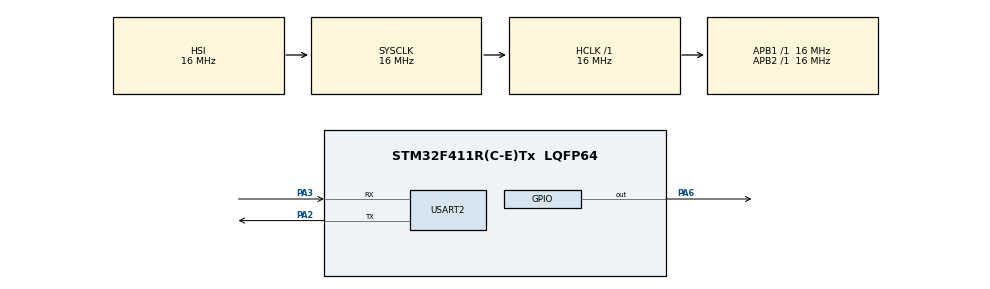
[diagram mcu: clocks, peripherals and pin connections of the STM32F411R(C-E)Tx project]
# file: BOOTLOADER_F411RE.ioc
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Mcu.Family=STM32F4
Mcu.Name=STM32F411R(C-E)Tx
Mcu.Package=LQFP64
NVIC.PriorityGroup=NVIC_PRIORITYGROUP_4
PA13.Mode=Serial_Wire
PA13.Signal=SYS_JTMS-SWDIO
PA14.Mode=Serial_Wire
PA14.Signal=SYS_JTCK-SWCLK
PA2.Mode=Asynchronous
PA2.Signal=USART2_TX
PA3.Mode=Asynchronous
PA3.Signal=USART2_RX
PA6.Signal=GPIO_Output
ProjectManager.HeapSize=0x200
ProjectManager.StackSize=0x400
ProjectManager.TargetToolchain=STM32CubeIDE
RCC.AHBFreq_Value=16000000
RCC.APB1Freq_Value=16000000
RCC.APB2Freq_Value=16000000
RCC.CortexFreq_Value=16000000
RCC.HSE_VALUE=25000000
RCC.HSI_VALUE=16000000
RCC.LSE_VALUE=32768
RCC.SYSCLKFreq_VALUE=16000000
RCC.VCOOutputFreq_Value=192000000
USART2.VirtualMode=VM_ASYNC
board=custom

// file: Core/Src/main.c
/* USER CODE END Header */
#include "main.h"

/* USER CODE BEGIN Includes */
#include "bl_jump.h"
#include <string.h>
#include "bl_ota.h"
#include "ota_image.h"
/* USER CODE END Includes */

UART_HandleTypeDef huart2;

void SystemClock_Config(void);
static void MX_GPIO_Init(void);
static void MX_USART2_UART_Init(void);

/* USER CODE BEGIN 0 */

static uint32_t mem_base = 0;  // used with external or dual flash
static uint32_t mem_cursor = 0;
static uint32_t ota_image_total_size = 16;  // expected OTA Header size

void ota_mem_set_total_size(uint32_t size)
{
    ota_image_total_size = size;
}

int ota_read_mem(uint8_t *buf, uint32_t len)
{
    if (mem_cursor + len > ota_image_total_size)
        return -1;

    memcpy(buf, &ota_image_bin[mem_base + mem_cursor], len);  // this function should be replaced accordingly

    mem_cursor += len;
    return 0;
}

/* USER CODE END 0 */

int main(void)
{

  /* MCU Configuration--------------------------------------------------------*/

  /* Reset of all peripherals, Initializes the Flash interface and the Systick. */
  HAL_Init();

  /* Configure the system clock */
  SystemClock_Config();

  /* Initialize all configured peripherals */
  MX_GPIO_Init();
  MX_USART2_UART_Init();
  /* USER CODE BEGIN 2 */

  HAL_Delay(100);

  HAL_UART_Transmit(&huart2, (uint8_t *)"Inside Bootloader!!\r\n", 21, 100);

  if (check_ota_request() == 0)
  {
	  HAL_UART_Transmit(&huart2, (uint8_t *)"Performing OTA...\n", 18, 100);

	  ota_stream_t stream =
	  {
	      .read = ota_read_mem,
	      .set_total_size = ota_mem_set_total_size
	  };

	  bl_ota_ctx_t ctx;
	 if (bl_ota_run(&ctx, &stream) != 0)
	 {
		 HAL_UART_Transmit(&huart2, (uint8_t *)"OTA Failed...\n", 14, 100);
		  while (1)
		  {
			  HAL_GPIO_TogglePin(GPIOA, GPIO_PIN_5);
			  HAL_Delay(250);
		  }
	 }
	 else {
		 HAL_UART_Transmit(&huart2, (uint8_t *)"OTA Flashed Successfully, Jumping to app...\n", 44, 100);
	 }

  }
  int err = bootloader_is_app_valid();
  if (err != 0)
  {
	  HAL_UART_Transmit(&huart2, (uint8_t *)"Failed to Jump!! ", 17, 100);
	  switch (err){
	  case 1:
		  HAL_UART_Transmit(&huart2, (uint8_t *)"MAGIC ERROR!!\r\n", 15, 100);
		  break;

	  case 2:
		  HAL_UART_Transmit(&huart2, (uint8_t *)"RESET ERROR!!\r\n", 15, 100);
		  break;

	  case 3:
		  HAL_UART_Transmit(&huart2, (uint8_t *)"SIZE ERROR!!\r\n", 14, 100);
		  break;

	  case 4:
		  HAL_UART_Transmit(&huart2, (uint8_t *)"CRC ERROR!!\r\n", 13, 100);
		  break;

	  default:
		  HAL_UART_Transmit(&huart2, (uint8_t *)"ERROR!!\r\n", 9, 100);
		  break;
	  }

	  while (1)
	  {
		  HAL_GPIO_TogglePin(GPIOA, GPIO_PIN_5);
		  HAL_Delay(100);
	  }
  }

  JumpToApplication();

  /* USER CODE END 2 */

  /* Infinite loop */
  while (1)
  {

  }
}

void SystemClock_Config(void)
{
  RCC_OscInitTypeDef RCC_OscInitStruct = {0};
  RCC_ClkInitTypeDef RCC_ClkInitStruct = {0};

  /** Configure the main internal regulator output voltage
  */
  __HAL_RCC_PWR_CLK_ENABLE();
  __HAL_PWR_VOLTAGESCALING_CONFIG(PWR_REGULATOR_VOLTAGE_SCALE3);

  /** Initializes the RCC Oscillators according to the specified parameters
  * in the RCC_OscInitTypeDef structure.
  */
  RCC_OscInitStruct.OscillatorType = RCC_OSCILLATORTYPE_HSI;
  RCC_OscInitStruct.HSIState = RCC_HSI_ON;
  RCC_OscInitStruct.HSICalibrationValue = RCC_HSICALIBRATION_DEFAULT;
  RCC_OscInitStruct.PLL.PLLState = RCC_PLL_NONE;
  if (HAL_RCC_OscConfig(&RCC_OscInitStruct) != HAL_OK)
  {
    Error_Handler();
  }

  /** Initializes the CPU, AHB and APB buses clocks
  */
  RCC_ClkInitStruct.ClockType = RCC_CLOCKTYPE_HCLK|RCC_CLOCKTYPE_SYSCLK
                              |RCC_CLOCKTYPE_PCLK1|RCC_CLOCKTYPE_PCLK2;
  RCC_ClkInitStruct.SYSCLKSource = RCC_SYSCLKSOURCE_HSI;
  RCC_ClkInitStruct.AHBCLKDivider = RCC_SYSCLK_DIV1;
  RCC_ClkInitStruct.APB1CLKDivider = RCC_HCLK_DIV1;
  RCC_ClkInitStruct.APB2CLKDivider = RCC_HCLK_DIV1;

  if (HAL_RCC_ClockConfig(&RCC_ClkInitStruct, FLASH_LATENCY_0) != HAL_OK)
  {
    Error_Handler();
  }
}

static void MX_USART2_UART_Init(void)
{

  huart2.Instance = USART2;
  huart2.Init.BaudRate = 115200;
  huart2.Init.WordLength = UART_WORDLENGTH_8B;
  huart2.Init.StopBits = UART_STOPBITS_1;
  huart2.Init.Parity = UART_PARITY_NONE;
  huart2.Init.Mode = UART_MODE_TX_RX;
  huart2.Init.HwFlowCtl = UART_HWCONTROL_NONE;
  huart2.Init.OverSampling = UART_OVERSAMPLING_16;
  if (HAL_UART_Init(&huart2) != HAL_OK)
  {
    Error_Handler();
  }

}

static void MX_GPIO_Init(void)
{
  GPIO_InitTypeDef GPIO_InitStruct = {0};

  /* GPIO Ports Clock Enable */
  __HAL_RCC_GPIOA_CLK_ENABLE();

  /*Configure GPIO pin Output Level */
  HAL_GPIO_WritePin(GPIOA, GPIO_PIN_5, GPIO_PIN_RESET);

  /*Configure GPIO pin : PA1 */
  GPIO_InitStruct.Pin = GPIO_PIN_1;
  GPIO_InitStruct.Mode = GPIO_MODE_INPUT;
  GPIO_InitStruct.Pull = GPIO_PULLUP;
  HAL_GPIO_Init(GPIOA, &GPIO_InitStruct);

  /*Configure GPIO pin : PA5 */
  GPIO_InitStruct.Pin = GPIO_PIN_5;
  GPIO_InitStruct.Mode = GPIO_MODE_OUTPUT_PP;
  GPIO_InitStruct.Pull = GPIO_NOPULL;
  GPIO_InitStruct.Speed = GPIO_SPEED_FREQ_LOW;
  HAL_GPIO_Init(GPIOA, &GPIO_InitStruct);

}

void Error_Handler(void)
{
  __disable_irq();
  while (1)
  {
  }
}
